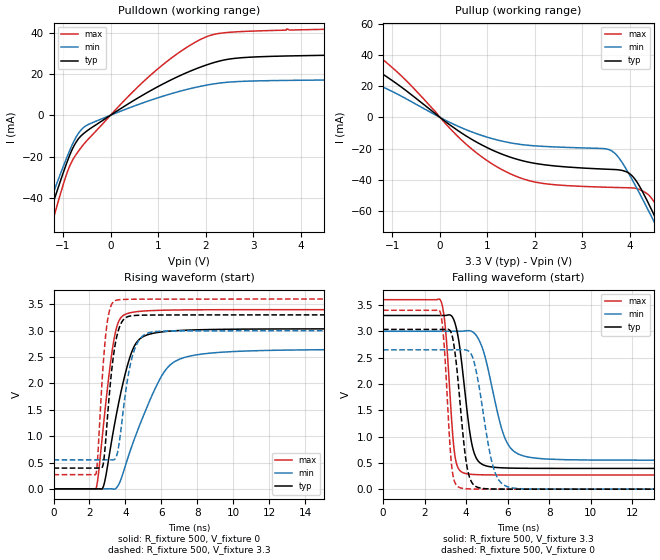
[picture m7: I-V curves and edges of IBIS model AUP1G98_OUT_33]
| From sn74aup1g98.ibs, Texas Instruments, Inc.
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[Model]   AUP1G98_OUT_33
Model_type  Output
Vref =   0
Rref =   1E6
Cref =   30p
Vmeas =   1.65
| variable   typ   min   max
C_comp   2.73pF   1.81pF   4.12pF
| C_pullup   3.12pF   1.81pF   4.12pF
| C_pulldown   2.33pF   2.13pF   2.90pF
[Temperature Range]   40   100   -40
| Ambient temperature   25   85   -40
[Voltage range]   3.3   3   3.6
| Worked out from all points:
|   slope of the pulldown table from 0 to 0.495 V, typ, clamps not added: 68.4 ohm
|   slope of the pullup table from 0 to 0.495 V, typ, clamps not added: 45.8 ohm
|   rising waveform, R_fixture 500, V_fixture 0: 20-80 % time 1.1ns typ, 1.9ns min, 688ps max; typ from 0 V to 3.04 V
|   falling waveform, R_fixture 500, V_fixture 3.3: 20-80 % time 536ps typ, 886ps min, 344ps max; typ from 3.3 V to 0.394 V
|   rising waveform, R_fixture 500, V_fixture 3.3: 20-80 % time 506ps typ, 664ps min, 393ps max; typ from 0.394 V to 3.3 V
|   falling waveform, R_fixture 500, V_fixture 0: 20-80 % time 456ps typ, 684ps min, 305ps max; typ from 3.04 V to 0 V
[Pulldown]
| AUP1G98_OUT_33
|   Voltage   I(typ)   I(min)   I(max)
-3.6V     -218.7mA   -196.3mA   -248.6mA
-1.515V   -64.37mA   -57.31mA   -75.82mA
-1.39V    -55.35mA   -49.29mA   -65.41mA
-1.275V   -47.14mA   -42mA      -55.89mA
-870mV    -19.93mA   -17.62mA   -25.18mA
-720mV    -12.85mA   -10.38mA   -18.82mA
-545mV    -8.444mA   -5.509mA   -13.51mA
940mV     13.13mA    8.018mA    21.36mA
1.5V      19.56mA    11.86mA    31.27mA
2.045V    24.53mA    14.67mA    38.2mA
3.1V      28.27mA    16.63mA    40.81mA
7.2V      29.73mA    17.36mA    42.67mA
[Pullup]
| AUP1G98_OUT_33
|   Voltage   I(typ)   I(min)   I(max)
-3.6V     42.88mA    27.27mA    57.92mA
-2.465V   31.53mA    19.52mA    45.85mA
-1.53V    32.87mA    22.09mA    44.95mA
-755mV    18.1mA     12.64mA    24.89mA
555mV     -11.98mA   -7.942mA   -17.3mA
1.65V     -27.07mA   -17.13mA   -38.31mA
3.61V     -33.32mA   -21.39mA   -44.82mA
4.08V     -38.63mA   -41.77mA   -45.28mA
4.375V    -54.25mA   -58.9mA    -49.24mA
4.565V    -66.24mA   -70.37mA   -57.33mA
4.775V    -80.02mA   -83.29mA   -71.37mA
7.2V      -250.7mA   -240.9mA   -257mA
[Ramp]
| AUP1G98_OUT_33
| variable   typ   min   max
dV/dt_r   1.82/1.10E-09   1.59/1.90E-09   2.04/6.90E-10
dV/dt_f   1.75/5.43E-10   1.48/8.93E-10   2.01/3.48E-10
R_load = 500
[Rising Waveform]
| AUP1G98_OUT_33
R_fixture =   500
C_fixture =   0
L_fixture =   0
V_fixture =   0
V_fixture_min = 0
V_fixture_max = 0
|   Time   V(typ)   V(min)   V(max)
0s        24.73nV    82.54nV    2.123nV
2.365ns   8.968uV    -3.169uV   8.959mV
2.8ns     73.18mV    -19.84uV   1.274V
3.37ns    1.175V     -5.237mV   2.841V
3.655ns   1.678V     100.1mV    3.196V
4.12ns    2.349V     569.7mV    3.327V
4.755ns   2.83V      1.173V     3.366V
6.035ns   2.977V     2.152V     3.388V
7.535ns   3.012V     2.515V     3.395V
30.7ns    3.035V     2.647V     3.399V
[Falling Waveform]
| AUP1G98_OUT_33
R_fixture =   500
C_fixture =   0
L_fixture =   0
V_fixture =   3.3
V_fixture_min = 3
V_fixture_max = 3.6
|   Time   V(typ)   V(min)   V(max)
0s        3.3V       3V         3.6V
2.785ns   3.3V       3V         3.578V
3.015ns   3.301V     3V         3.014V
3.445ns   3.179V     3V         682.3mV
3.92ns    1.933V     3.005V     302.8mV
4.245ns   920.9mV    3.002V     282.1mV
4.575ns   537.6mV    2.868V     274.9mV
5.86ns    403.5mV    978.4mV    269.7mV
6.87ns    396.4mV    620.2mV    269.4mV
30.7ns    394.1mV    550mV      269.3mV
[Rising Waveform]
| AUP1G98_OUT_33
R_fixture =   500
C_fixture =   0
L_fixture =   0
V_fixture =   3.3
V_fixture_min = 3
V_fixture_max = 3.6
|   Time   V(typ)   V(min)   V(max)
0s        394.1mV    550mV      269.3mV
2.36ns    394.1mV    550mV      282.1mV
2.465ns   394.4mV    550mV      632.9mV
2.745ns   437.5mV    550mV      2.264V
2.935ns   1.056V     550.2mV    3.012V
3.22ns    2.194V     550.5mV    3.49V
3.495ns   2.85V      612.5mV    3.578V
4.375ns   3.284V     2.498V     3.597V
5.36ns    3.296V     2.967V     3.599V
30.7ns    3.3V       3V         3.6V
[Falling Waveform]
| AUP1G98_OUT_33
R_fixture =   500
C_fixture =   0
L_fixture =   0
V_fixture =   0
V_fixture_min = 0
V_fixture_max = 0
|   Time   V(typ)   V(min)   V(max)
0s        3.035V     2.647V     3.399V
2.74ns    3.035V     2.647V     3.38V
2.935ns   3.035V     2.647V     2.779V
3.315ns   2.933V     2.647V     407.5mV
3.735ns   1.519V     2.648V     23.26mV
4.005ns   515.7mV    2.643V     8.137mV
4.28ns    124.2mV    2.538V     3.351mV
5.295ns   3.303mV    433.4mV    189.4uV
6.095ns   527.9uV    33.82mV    32.85uV
30.7ns    -26.07nV   45.68nV    -34.58nV
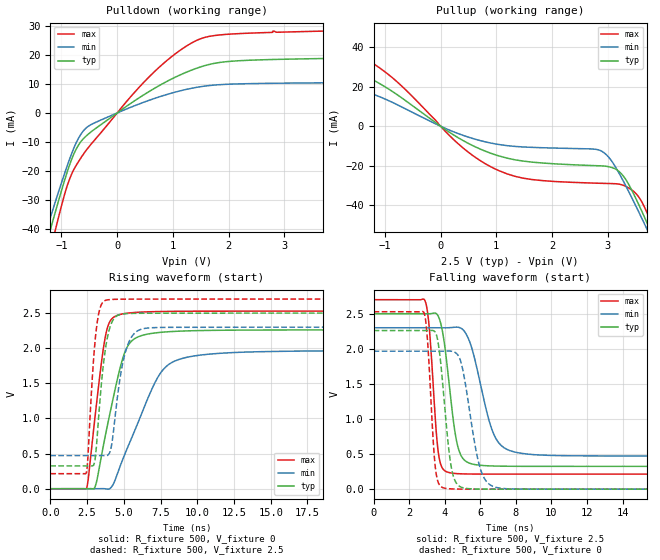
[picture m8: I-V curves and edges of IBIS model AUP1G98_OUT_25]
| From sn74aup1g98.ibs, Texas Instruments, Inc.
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[Model]   AUP1G98_OUT_25
Model_type  Output
Vref =   0
Rref =   1E6
Cref =   30p
Vmeas =   1.25
| variable   typ   min   max
C_comp   2.77pF   1.87pF   4.14pF
| C_pullup   3.12pF   1.87pF   4.14pF
| C_pulldown   2.42pF   2.13pF   2.99pF
[Temperature Range]   40   100   -40
| Ambient temperature   25   85   -40
[Voltage range]   2.5   2.3   2.7
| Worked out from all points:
|   slope of the pulldown table from 0 to 0.375 V, typ, clamps not added: 75.2 ohm
|   slope of the pullup table from 0 to 0.375 V, typ, clamps not added: 55.1 ohm
|   rising waveform, R_fixture 500, V_fixture 0: 20-80 % time 1.4ns typ, 2.39ns min, 856ps max; typ from 0 V to 2.26 V
|   falling waveform, R_fixture 500, V_fixture 2.5: 20-80 % time 625ps typ, 1.07ns min, 396ps max; typ from 2.5 V to 0.325 V
|   rising waveform, R_fixture 500, V_fixture 2.5: 20-80 % time 611ps typ, 786ps min, 469ps max; typ from 0.325 V to 2.5 V
|   falling waveform, R_fixture 500, V_fixture 0: 20-80 % time 515ps typ, 782ps min, 343ps max; typ from 2.26 V to 0 V
[Pulldown]
| AUP1G98_OUT_25
|   Voltage   I(typ)   I(min)   I(max)
-3.6V     -214mA     -193.5mA   -239.7mA
-1.26V    -44.55mA   -39.92mA   -52.42mA
-1.205V   -40.74mA   -36.52mA   -48.02mA
-1.115V   -34.57mA   -31.02mA   -40.91mA
-800mV    -15.22mA   -13.22mA   -20.4mA
-685mV    -10.84mA   -8.445mA   -16.54mA
-540mV    -7.689mA   -4.911mA   -12.5mA
675mV     8.558mA    5.038mA    14.35mA
1.105V    12.9mA     7.5mA      21.28mA
1.52V     16.03mA    9.129mA    25.76mA
2.585V    18.34mA    10.19mA    27.69mA
7.2V      19.61mA    10.73mA    29.61mA
[Pullup]
| AUP1G98_OUT_25
|   Voltage   I(typ)   I(min)   I(max)
-3.6V     37.28mA    23.5mA     50.35mA
-2.355V   24.65mA    15.21mA    35.57mA
-1.425V   26.01mA    17.2mA     35.58mA
-760mV    15.58mA    10.63mA    21.96mA
405mV     -7.279mA   -4.651mA   -11.04mA
1.05V     -15.07mA   -9.293mA   -22.54mA
2.845V    -20.04mA   -12.07mA   -28.88mA
3.17V     -22.17mA   -22.09mA   -29.2mA
3.455V    -33.67mA   -37.48mA   -32.73mA
3.685V    -47.61mA   -50.92mA   -42.5mA
3.82V     -56.28mA   -59.04mA   -51.47mA
7.2V      -294.7mA   -278.7mA   -311.5mA
[Ramp]
| AUP1G98_OUT_25
| variable   typ   min   max
dV/dt_r   1.36/1.40E-09   1.18/2.40E-09   1.52/8.57E-10
dV/dt_f   1.31/6.33E-10   1.10/1.07E-09   1.50/4.06E-10
R_load = 500
[Rising Waveform]
| AUP1G98_OUT_25
R_fixture =   500
C_fixture =   0
L_fixture =   0
V_fixture =   0
V_fixture_min = 0
V_fixture_max = 0
|   Time   V(typ)   V(min)   V(max)
0s        19.04nV    76.96nV    1.464nV
2.47ns    -20.63uV   43.8nV     8.222mV
3.07ns    40.86mV    -29.67uV   1.068V
3.72ns    727.7mV    -199.1uV   2.134V
4.575ns   1.568V     217.8mV    2.469V
5.105ns   1.959V     508.2mV    2.495V
5.66ns    2.125V     784.2mV    2.508V
7.42ns    2.224V     1.622V     2.522V
8.905ns   2.244V     1.851V     2.526V
32.79ns   2.261V     1.966V     2.528V
[Falling Waveform]
| AUP1G98_OUT_25
R_fixture =   500
C_fixture =   0
L_fixture =   0
V_fixture =   2.5
V_fixture_min = 2.3
V_fixture_max = 2.7
|   Time   V(typ)   V(min)   V(max)
0s        2.5V       2.3V       2.7V
2.895ns   2.5V       2.3V       2.683V
3.135ns   2.499V     2.3V       2.285V
3.64ns    2.463V     2.3V       519.8mV
4.2ns     1.612V     2.3V       239.2mV
4.615ns   753.7mV    2.308V     222.8mV
5.005ns   443mV      2.277V     217.9mV
6.73ns    330.1mV    800mV      214.5mV
7.895ns   326mV      531.8mV    214.4mV
32.79ns   324.7mV    472mV      214.4mV
[Rising Waveform]
| AUP1G98_OUT_25
R_fixture =   500
C_fixture =   0
L_fixture =   0
V_fixture =   2.5
V_fixture_min = 2.3
V_fixture_max = 2.7
|   Time   V(typ)   V(min)   V(max)
0s        324.7mV    472mV      214.4mV
2.455ns   324.7mV    472mV      227.4mV
2.945ns   332.9mV    472mV      1.838V
3.115ns   545.3mV    472mV      2.238V
3.39ns    1.282V     472.4mV    2.574V
3.77ns    2.015V     471.1mV    2.682V
4.15ns    2.35V      596.9mV    2.694V
5.11ns    2.492V     1.944V     2.698V
6.205ns   2.498V     2.272V     2.699V
32.79ns   2.5V       2.3V       2.7V
[Falling Waveform]
| AUP1G98_OUT_25
R_fixture =   500
C_fixture =   0
L_fixture =   0
V_fixture =   0
V_fixture_min = 0
V_fixture_max = 0
|   Time   V(typ)   V(min)   V(max)
0s        2.261V     1.966V     2.528V
2.835ns   2.261V     1.966V     2.512V
3.035ns   2.26V      1.966V     2.105V
3.47ns    2.234V     1.966V     312.7mV
3.945ns   1.331V     1.966V     17.07mV
4.29ns    441.5mV    1.968V     5.176mV
4.615ns   101.5mV    1.944V     1.881mV
5.985ns   1.381mV    306.3mV    53.78uV
6.87ns    238.3uV    25.85mV    10.3uV
32.79ns   -19.76nV   27.44nV    -30.47nV
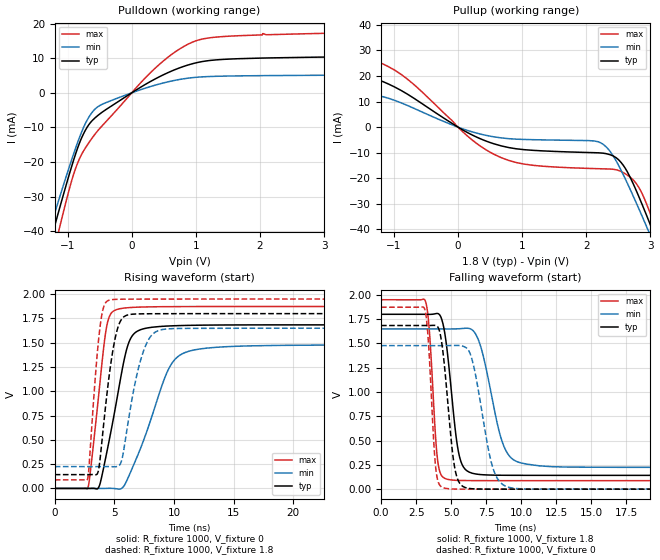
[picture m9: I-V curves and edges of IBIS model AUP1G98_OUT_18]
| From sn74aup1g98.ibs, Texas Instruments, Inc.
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[Model]   AUP1G98_OUT_18
Model_type  Output
Vref =   0
Rref =   1E6
Cref =   30p
Vmeas =   0.9
| variable   typ   min   max
C_comp   2.80pF   1.94pF   4.08pF
| C_pullup   3.08pF   1.94pF   4.08pF
| C_pulldown   2.52pF   2.14pF   3.04pF
[Temperature Range]   40   100   -40
| Ambient temperature   25   85   -40
[Voltage range]   1.8   1.65   1.95
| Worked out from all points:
|   slope of the pulldown table from 0 to 0.27 V, typ, clamps not added: 88.6 ohm
|   slope of the pullup table from 0 to 0.27 V, typ, clamps not added: 73.6 ohm
|   rising waveform, R_fixture 1000, V_fixture 0: 20-80 % time 1.56ns typ, 2.57ns min, 978ps max; typ from 0 V to 1.68 V
|   falling waveform, R_fixture 1000, V_fixture 1.8: 20-80 % time 738ps typ, 1.29ns min, 457ps max; typ from 1.8 V to 0.142 V
|   rising waveform, R_fixture 1000, V_fixture 1.8: 20-80 % time 996ps typ, 1.38ns min, 709ps max; typ from 0.142 V to 1.8 V
|   falling waveform, R_fixture 1000, V_fixture 0: 20-80 % time 667ps typ, 1.1ns min, 424ps max; typ from 1.68 V to 0 V
[Pulldown]
| AUP1G98_OUT_18
|   Voltage   I(typ)   I(min)   I(max)
-3.6V     -208.6mA   -189.9mA   -231.7mA
-1.27V    -43.16mA   -39.01mA   -50.14mA
-1.215V   -39.42mA   -35.66mA   -45.88mA
-1.125V   -33.38mA   -30.25mA   -38.97mA
-850mV    -16.31mA   -14.68mA   -20.63mA
-710mV    -10.41mA   -8.408mA   -15.6mA
-555mV    -6.973mA   -4.411mA   -11.55mA
360mV     3.96mA     2.185mA    7.039mA
705mV     6.927mA    3.722mA    12.18mA
1.03V     8.784mA    4.527mA    15.22mA
2.04V     10.05mA    4.966mA    17.1mA
7.2V      11.18mA    5.355mA    18.77mA
[Pullup]
| AUP1G98_OUT_18
|   Voltage   I(typ)   I(min)   I(max)
-3.6V     32.09mA    19.71mA    43.84mA
-3.16V    27.19mA    16.62mA    37.96mA
-2.12V    17.93mA    10.78mA    26.5mA
-1.525V   19.29mA    11.78mA    27.75mA
-1.155V   17.65mA    11.82mA    24.55mA
680mV     -7.373mA   -4.228mA   -12mA
2.185V    -10.05mA   -5.721mA   -16.26mA
2.485V    -12.35mA   -14.1mA    -16.81mA
2.725V    -21.81mA   -26.61mA   -20.47mA
2.94V     -34.55mA   -38.91mA   -30.08mA
3.085V    -43.74mA   -47.5mA    -39.77mA
7.2V      -334.8mA   -315.6mA   -357.6mA
[Ramp]
| AUP1G98_OUT_18
| variable   typ   min   max
dV/dt_r   1.01/1.56E-09   0.89/2.58E-09   1.13/9.81E-10
dV/dt_f   1.00/7.45E-10   0.86/1.30E-09   1.12/4.62E-10
R_load = 1000
[Rising Waveform]
| AUP1G98_OUT_18
R_fixture =   1000
C_fixture =   0
L_fixture =   0
V_fixture =   0
V_fixture_min = 0
V_fixture_max = 0
|   Time   V(typ)   V(min)   V(max)
0s        17.12nV    87.22nV    1.127nV
2.78ns    -23.81uV   -36.59nV   7.813mV
3.67ns    8.984mV    -20.25uV   948.4mV
4.275ns   319.6mV    376.1uV    1.613V
5.095ns   841mV      -2.406mV   1.838V
5.95ns    1.396V     57.58mV    1.859V
6.58ns    1.585V     232mV      1.865V
9.45ns    1.672V     1.206V     1.872V
10.94ns   1.678V     1.4V       1.873V
35.9ns    1.685V     1.477V     1.873V
[Falling Waveform]
| AUP1G98_OUT_18
R_fixture =   1000
C_fixture =   0
L_fixture =   0
V_fixture =   1.8
V_fixture_min = 1.65
V_fixture_max = 1.95
|   Time   V(typ)   V(min)   V(max)
0s        1.8V       1.65V      1.95V
3.165ns   1.8V       1.65V      1.936V
3.445ns   1.799V     1.65V      1.635V
4.02ns    1.808V     1.65V      319.3mV
4.62ns    1.537V     1.649V     107mV
5.52ns    387.2mV    1.651V     90mV
6.46ns    166.2mV    1.644V     88.23mV
8.665ns   143.2mV    479.3mV    87.9mV
9.805ns   142.5mV    277.6mV    87.9mV
35.9ns    142.2mV    224.7mV    87.89mV
[Rising Waveform]
| AUP1G98_OUT_18
R_fixture =   1000
C_fixture =   0
L_fixture =   0
V_fixture =   1.8
V_fixture_min = 1.65
V_fixture_max = 1.95
|   Time   V(typ)   V(min)   V(max)
0s        142.2mV    224.7mV    87.89mV
2.76ns    142.2mV    224.7mV    99.88mV
3.755ns   257.7mV    224.7mV    1.622V
4.08ns    638.5mV    224.8mV    1.861V
4.505ns   1.107V     225.3mV    1.936V
5.07ns    1.55V      223.2mV    1.947V
5.62ns    1.745V     294.3mV    1.948V
7.175ns   1.798V     1.311V     1.95V
8.695ns   1.799V     1.626V     1.95V
35.9ns    1.8V       1.65V      1.95V
[Falling Waveform]
| AUP1G98_OUT_18
R_fixture =   1000
C_fixture =   0
L_fixture =   0
V_fixture =   0
V_fixture_min = 0
V_fixture_max = 0
|   Time   V(typ)   V(min)   V(max)
0s        1.685V     1.478V     1.873V
3.125ns   1.684V     1.478V     1.849V
3.375ns   1.684V     1.478V     1.525V
3.89ns    1.685V     1.477V     235.9mV
4.42ns    1.409V     1.477V     15.75mV
5.225ns   246.8mV    1.48V      1.38mV
6.03ns    15.68mV    1.46V      150.6uV
7.95ns    215.4uV    233.2mV    3.425uV
9.02ns    44.82uV    23.16mV    655.1nV
35.9ns    7.596nV    48.19nV    -58.74nV
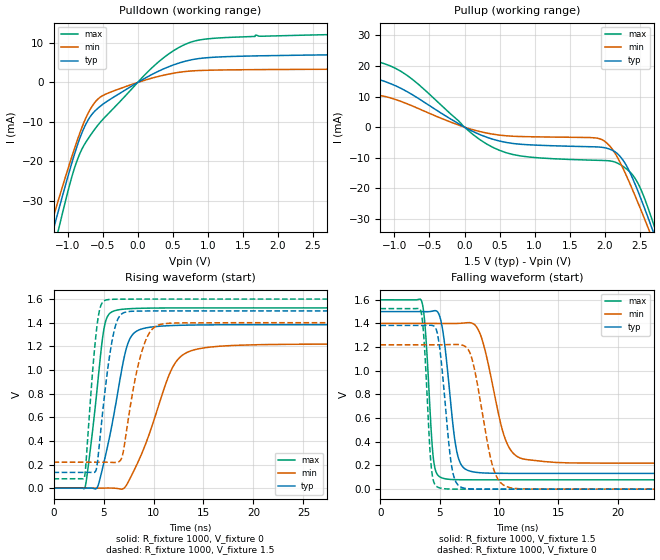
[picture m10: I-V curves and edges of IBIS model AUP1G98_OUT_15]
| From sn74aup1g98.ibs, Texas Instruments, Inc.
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[Model]   AUP1G98_OUT_15
Model_type  Output
Vref =   0
Rref =   1E6
Cref =   30p
Vmeas =   0.75
| variable   typ   min   max
C_comp   2.79pF   1.99pF   4.00pF
| C_pullup   3.03pF   1.99pF   4.00pF
| C_pulldown   2.56pF   2.15pF   3.05pF
[Temperature Range]   40   100   -40
| Ambient temperature   25   85   -40
[Voltage range]   1.5   1.4   1.6
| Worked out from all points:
|   slope of the pulldown table from 0 to 0.225 V, typ, clamps not added: 101 ohm
|   slope of the pullup table from 0 to 0.225 V, typ, clamps not added: 90.4 ohm
|   rising waveform, R_fixture 1000, V_fixture 0: 20-80 % time 1.86ns typ, 3.07ns min, 1.18ns max; typ from 0 V to 1.38 V
|   falling waveform, R_fixture 1000, V_fixture 1.5: 20-80 % time 874ps typ, 1.57ns min, 528ps max; typ from 1.5 V to 0.133 V
|   rising waveform, R_fixture 1000, V_fixture 1.5: 20-80 % time 1.19ns typ, 1.61ns min, 855ps max; typ from 0.133 V to 1.5 V
|   falling waveform, R_fixture 1000, V_fixture 0: 20-80 % time 790ps typ, 1.33ns min, 489ps max; typ from 1.38 V to 0 V
[Pulldown]
| AUP1G98_OUT_15
|   Voltage   I(typ)   I(min)   I(max)
-3.6V     -206.1mA   -188.4mA   -227.8mA
-1.265V   -41.59mA   -37.94mA   -47.65mA
-1.21V    -37.9mA    -34.62mA   -43.48mA
-1.11V    -31.29mA   -28.67mA   -36mA
-945mV    -20.84mA   -19.21mA   -24.37mA
-855mV    -15.7mA    -14.39mA   -19.43mA
-720mV    -9.972mA   -8.297mA   -14.65mA
-570mV    -6.595mA   -4.269mA   -10.91mA
260mV     2.544mA    1.373mA    4.642mA
810mV     5.906mA    2.979mA    10.53mA
1.685V    6.762mA    3.268mA    12.01mA
7.2V      7.827mA    3.609mA    13.77mA
[Pullup]
| AUP1G98_OUT_15
|   Voltage   I(typ)   I(min)   I(max)
-3.6V     29.66mA    17.95mA    40.7mA
-2.925V   22.54mA    13.64mA    31.9mA
-2.13V    15.77mA    9.503mA    23.16mA
-1.025V   13.91mA    9.322mA    19.64mA
130mV     -1.525mA   -910.1uA   -2.565mA
590mV     -4.979mA   -2.819mA   -8.32mA
1.925V    -6.506mA   -3.765mA   -10.85mA
2.175V    -8.513mA   -9.57mA    -11.67mA
2.395V    -16.55mA   -20.31mA   -15.49mA
2.615V    -29.32mA   -32.63mA   -26.15mA
2.72V     -35.89mA   -38.74mA   -33.2mA
7.2V      -352.6mA   -330.3mA   -379.5mA
[Ramp]
| AUP1G98_OUT_15
| variable   typ   min   max
dV/dt_r   0.83/1.88E-09   0.74/3.10E-09   0.92/1.19E-09
dV/dt_f   0.83/8.82E-10   0.71/1.58E-09   0.92/5.32E-10
R_load = 1000
[Rising Waveform]
| AUP1G98_OUT_15
R_fixture =   1000
C_fixture =   0
L_fixture =   0
V_fixture =   0
V_fixture_min = 0
V_fixture_max = 0
|   Time   V(typ)   V(min)   V(max)
0s        16.57nV    92.2nV     986.7pV
3.15ns    -28.21uV   -326.5nV   7.591mV
4.34ns    1.184mV    -21.34uV   823.4mV
4.98ns    196.1mV    129.5uV    1.315V
5.865ns   544mV      487.9uV    1.493V
7.095ns   1.118V     3.103mV    1.515V
7.845ns   1.293V     114.4mV    1.519V
11.69ns   1.375V     984mV      1.525V
13.32ns   1.379V     1.147V     1.525V
34.99ns   1.383V     1.22V      1.525V
[Falling Waveform]
| AUP1G98_OUT_15
R_fixture =   1000
C_fixture =   0
L_fixture =   0
V_fixture =   1.5
V_fixture_min = 1.4
V_fixture_max = 1.6
|   Time   V(typ)   V(min)   V(max)
0s        1.5V       1.4V       1.6V
3.48ns    1.5V       1.4V       1.587V
4.46ns    1.506V     1.4V       266.7mV
5.125ns   1.413V     1.4V       98mV
6.375ns   352.5mV    1.4V       80.25mV
7.33ns    160.4mV    1.407V     79.28mV
8.425ns   138.7mV    1.308V     79.11mV
10.4ns    133.6mV    459mV      79.08mV
11.74ns   133.3mV    264.8mV    79.08mV
34.99ns   133.1mV    219.3mV    79.08mV
[Rising Waveform]
| AUP1G98_OUT_15
R_fixture =   1000
C_fixture =   0
L_fixture =   0
V_fixture =   1.5
V_fixture_min = 1.4
V_fixture_max = 1.6
|   Time   V(typ)   V(min)   V(max)
0s        133.1mV    219.3mV    79.08mV
3.07ns    133.1mV    219.3mV    84.58mV
4.27ns    156.7mV    219.3mV    1.317V
5.11ns    793.5mV    219.6mV    1.587V
5.86ns    1.247V     217.8mV    1.598V
6.545ns   1.448V     224.3mV    1.599V
6.95ns    1.482V     298mV      1.599V
8.72ns    1.499V     1.124V     1.6V
10.37ns   1.5V       1.376V     1.6V
34.99ns   1.5V       1.4V       1.6V
[Falling Waveform]
| AUP1G98_OUT_15
R_fixture =   1000
C_fixture =   0
L_fixture =   0
V_fixture =   0
V_fixture_min = 0
V_fixture_max = 0
|   Time   V(typ)   V(min)   V(max)
0s        1.383V     1.22V      1.525V
3.4ns     1.383V     1.22V      1.508V
4.29ns    1.384V     1.22V      185.8mV
4.88ns    1.274V     1.219V     14.87mV
5.98ns    211.4mV    1.222V     729.6uV
6.825ns   15.66mV    1.219V     83.1uV
7.775ns   1.711mV    1.08V      11.98uV
9.52ns    82.62uV    176.5mV    900.4nV
10.6ns    20.7uV     22.8mV     289.2nV
34.99ns   -21.64nV   53.06nV    -50.8nV
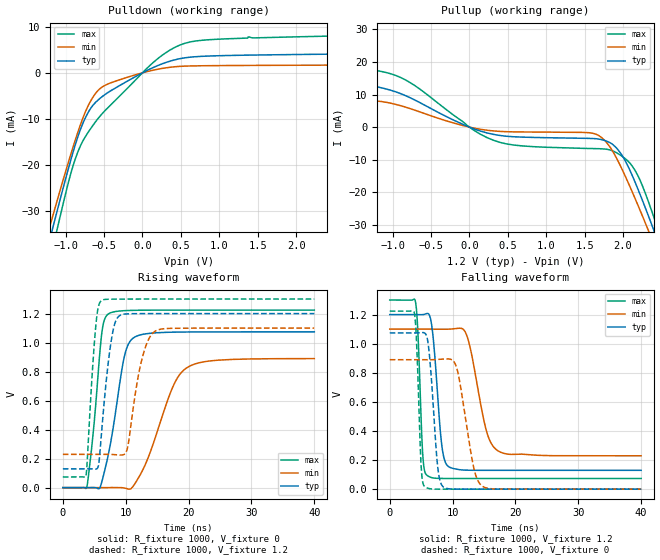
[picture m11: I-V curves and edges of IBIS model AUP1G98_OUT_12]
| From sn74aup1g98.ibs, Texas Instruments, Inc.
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[Model]   AUP1G98_OUT_12
Model_type  Output
Vref =   0
Rref =   1E6
Cref =   30p
Vmeas =   0.6
| variable   typ   min   max
C_comp   2.77pF   2.03pF   3.84pF
| C_pullup   2.95pF   2.03pF   3.84pF
| C_pulldown   2.59pF   2.14pF   3.08pF
[Temperature Range]   40   100   -40
| Ambient temperature   25   85   -40
[Voltage range]   1.2   1.1   1.3
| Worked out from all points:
|   slope of the pulldown table from 0 to 0.18 V, typ, clamps not added: 125 ohm
|   slope of the pullup table from 0 to 0.18 V, typ, clamps not added: 123 ohm
|   rising waveform, R_fixture 1000, V_fixture 0: 20-80 % time 2.41ns typ, 4.38ns min, 1.48ns max; typ from 0 V to 1.07 V
|   falling waveform, R_fixture 1000, V_fixture 1.2: 20-80 % time 1.14ns typ, 2.34ns min, 646ps max; typ from 1.2 V to 0.129 V
|   rising waveform, R_fixture 1000, V_fixture 1.2: 20-80 % time 1.51ns typ, 2.09ns min, 1.07ns max; typ from 0.129 V to 1.2 V
|   falling waveform, R_fixture 1000, V_fixture 0: 20-80 % time 1.05ns typ, 1.98ns min, 601ps max; typ from 1.07 V to 0 V
[Pulldown]
| AUP1G98_OUT_12
|   Voltage   I(typ)   I(min)   I(max)
-3.6V     -203.6mA   -186.6mA   -224.6mA
-1.215V   -36.77mA   -33.88mA   -41.55mA
-1.165V   -33.49mA   -30.92mA   -37.89mA
-1.12V    -30.57mA   -28.28mA   -34.63mA
-1.08V    -28mA      -25.95mA   -31.76mA
-930mV    -18.76mA   -17.53mA   -21.68mA
-820mV    -12.87mA   -11.86mA   -16.33mA
-695mV    -8.261mA   -6.747mA   -12.62mA
-580mV    -5.938mA   -3.862mA   -9.962mA
160mV     1.298mA    643.5uA    2.533mA
610mV     3.376mA    1.481mA    6.659mA
7.2V      4.761mA    1.852mA    9.574mA
[Pullup]
| AUP1G98_OUT_12
|   Voltage   I(typ)   I(min)   I(max)
-3.6V     26.64mA    8.226mA    37.8mA
-3.065V   21.41mA    10.49mA    30.92mA
-2.05V    13.06mA    7.529mA    19.66mA
-955mV    10.79mA    6.951mA    15.81mA
400mV     -2.561mA   -1.314mA   -4.679mA
1.61V     -3.491mA   -1.891mA   -6.566mA
1.87V     -5.387mA   -7.563mA   -7.321mA
2.095V    -13.49mA   -18.49mA   -11.17mA
2.33V     -27.16mA   -31.66mA   -22.8mA
2.44V     -34.07mA   -38.08mA   -30.25mA
2.51V     -38.55mA   -42.22mA   -35.17mA
7.2V      -371mA     -348.5mA   -398.6mA
[Ramp]
| AUP1G98_OUT_12
| variable   typ   min   max
dV/dt_r   0.65/2.43E-09   0.54/4.44E-09   0.74/1.49E-09
dV/dt_f   0.65/1.15E-09   0.53/2.35E-09   0.74/6.51E-10
R_load = 1000
[Rising Waveform]
| AUP1G98_OUT_12
R_fixture =   1000
C_fixture =   0
L_fixture =   0
V_fixture =   0
V_fixture_min = 0
V_fixture_max = 0
|   Time   V(typ)   V(min)   V(max)
0s        17.04nV    106.6nV    899pV
3.805ns   -18.26uV   23.67nV    2.899mV
4.855ns   495.2uV    228.2nV    389.6mV
6.18ns    37.15mV    -16.22uV   1.06V
7.225ns   226.2mV    125.3uV    1.197V
9.76ns    898.9mV    -2.433mV   1.22V
11.39ns   1.037V     22.46mV    1.222V
17.54ns   1.072V     698.7mV    1.224V
19.62ns   1.073V     823.5mV    1.224V
40ns      1.074V     889.6mV    1.224V
[Falling Waveform]
| AUP1G98_OUT_12
R_fixture =   1000
C_fixture =   0
L_fixture =   0
V_fixture =   1.2
V_fixture_min = 1.1
V_fixture_max = 1.3
|   Time   V(typ)   V(min)   V(max)
0s        1.2V       1.1V       1.3V
4.08ns    1.2V       1.1V       1.291V
5.27ns    1.2V       1.1V       226.4mV
6ns       1.208V     1.1V       92.82mV
6.845ns   1.068V     1.1V       77.57mV
8.325ns   287.7mV    1.1V       73.79mV
9.33ns    155.6mV    1.1V       73.59mV
12.19ns   130.7mV    1.064V     73.54mV
17.19ns   129.5mV    264.2mV    73.54mV
40ns      129.5mV    229.3mV    73.54mV
[Rising Waveform]
| AUP1G98_OUT_12
R_fixture =   1000
C_fixture =   0
L_fixture =   0
V_fixture =   1.2
V_fixture_min = 1.1
V_fixture_max = 1.3
|   Time   V(typ)   V(min)   V(max)
0s        129.5mV    229.3mV    73.54mV
3.67ns    129.5mV    229.3mV    79.48mV
5.18ns    127.8mV    229.3mV    1.086V
6.135ns   367.9mV    229.3mV    1.29V
7.68ns    1.008V     229.2mV    1.299V
9.095ns   1.188V     225mV      1.3V
10.23ns   1.198V     265.1mV    1.3V
12.46ns   1.2V       864.7mV    1.3V
14.66ns   1.2V       1.078V     1.3V
40ns      1.2V       1.1V       1.3V
[Falling Waveform]
| AUP1G98_OUT_12
R_fixture =   1000
C_fixture =   0
L_fixture =   0
V_fixture =   0
V_fixture_min = 0
V_fixture_max = 0
|   Time   V(typ)   V(min)   V(max)
0s        1.074V     889.8mV    1.224V
3.945ns   1.074V     889.8mV    1.204V
5.01ns    1.076V     889.8mV    150.2mV
5.62ns    1.071V     889.7mV    15.47mV
6.325ns   917.4mV    889.6mV    3.696mV
7.67ns    139.5mV    892.1mV    143.5uV
8.585ns   13mV       894.1mV    19.29uV
10.66ns   318.5uV    833.5mV    714nV
14.77ns   2.489uV    18.98mV    -43.91nV
40ns      -13.74nV   85.05nV    -43.97nV
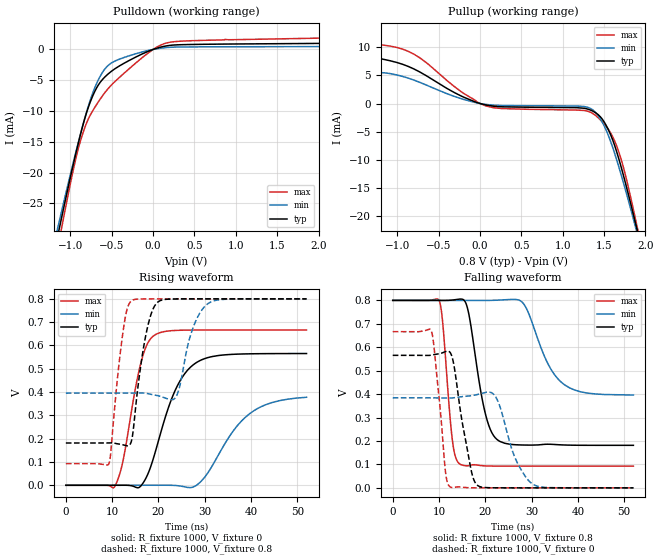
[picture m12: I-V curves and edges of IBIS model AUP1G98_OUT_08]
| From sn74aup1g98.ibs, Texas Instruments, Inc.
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[Model]   AUP1G98_OUT_08
Model_type  Output
Vref =   0
Rref =   1E6
Cref =   30p
Vmeas =   0.4
| variable   typ   min   max
C_comp   2.62pF   2.11pF   3.26pF
| C_pullup   2.68pF   2.11pF   3.26pF
| C_pulldown   2.55pF   2.11pF   2.99pF
[Temperature Range]   40   100   -40
| Ambient temperature   25   85   -40
[Voltage range]   0.8   0.8   0.8
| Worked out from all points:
|   slope of the pulldown table from 0 to 0.12 V, typ, clamps not added: 257 ohm
|   slope of the pullup table from 0 to 0.12 V, typ, clamps not added: 309 ohm
|   rising waveform, R_fixture 1000, V_fixture 0: 20-80 % time 5.93ns typ, 8.01ns min, 3.69ns max; typ from 0 V to 0.565 V
|   falling waveform, R_fixture 1000, V_fixture 0.8: 20-80 % time 3.16ns typ, 5.34ns min, 1.71ns max; typ from 0.8 V to 0.181 V
|   rising waveform, R_fixture 1000, V_fixture 0.8: 20-80 % time 2.7ns typ, 3.27ns min, 2.25ns max; typ from 0.181 V to 0.8 V
|   falling waveform, R_fixture 1000, V_fixture 0: 20-80 % time 2.81ns typ, 4ns min, 1.83ns max; typ from 0.566 V to 0 V
[Pulldown]
| AUP1G98_OUT_08
|   Voltage   I(typ)   I(min)   I(max)
-3.6V     -200.3mA   -184.7mA   -219.1mA
-1.155V   -30.43mA   -29.11mA   -32.45mA
-1.105V   -27.26mA   -26.22mA   -28.93mA
-940mV    -17.24mA   -17.01mA   -18.09mA
-865mV    -13.13mA   -13.1mA    -14.27mA
-745mV    -8.043mA   -7.657mA   -10.32mA
-630mV    -5.174mA   -4.128mA   -7.88mA
-470mV    -3.218mA   -1.946mA   -5.328mA
5mV       23.8uA     12.51uA    45.54uA
245mV     711.3uA    371.9uA    1.246mA
870mV     872.1uA    431.7uA    1.618mA
7.2V      1.459mA    578.6uA    3.138mA
[Pullup]
| AUP1G98_OUT_08
|   Voltage   I(typ)   I(min)   I(max)
-3.6V     2.784mA    339.2uA    9.474mA
-2.56V    3.921mA    663.8uA    11.14mA
-2.01V    6.261mA    1.269mA    13.37mA
-1.185V   7.906mA    5.477mA    10.41mA
-800mV    6.149mA    4.169mA    8.776mA
80mV      -287uA     -177.3uA   -461.9uA
1.285V    -921uA     -607uA     -1.305mA
1.455V    -2.355mA   -2.736mA   -2.902mA
1.625V    -7.333mA   -8.725mA   -6.56mA
1.74V     -13.09mA   -14.38mA   -11.68mA
1.905V    -22.78mA   -23.32mA   -22.23mA
7.2V      -396.8mA   -367.4mA   -431.7mA
[Ramp]
| AUP1G98_OUT_08
| variable   typ   min   max
dV/dt_r   0.35/5.99E-09   0.23/8.13E-09   0.41/3.74E-09
dV/dt_f   0.37/3.17E-09   0.24/5.36E-09   0.43/1.72E-09
R_load = 1000
[Rising Waveform]
| AUP1G98_OUT_08
R_fixture =   1000
C_fixture =   0
L_fixture =   0
V_fixture =   0
V_fixture_min = 0
V_fixture_max = 0
|   Time   V(typ)   V(min)   V(max)
0s        23.71nV    153.5nV    1.008nV
10.58ns   293.4uV    -25.4nV    -4.717mV
12.33ns   197uV      -1.998uV   103.3mV
16.28ns   -999.3uV   29.67uV    530.8mV
17.63ns   44.12mV    275.6uV    607.3mV
19.2ns    134.1mV    111.4uV    644.6mV
23.58ns   405.6mV    -750.2uV   664.4mV
28.07ns   524.8mV    -1.837mV   666.2mV
39.45ns   564mV      303.2mV    666.5mV
52ns      565.4mV    377.7mV    666.5mV
[Falling Waveform]
| AUP1G98_OUT_08
R_fixture =   1000
C_fixture =   0
L_fixture =   0
V_fixture =   0.8
V_fixture_min = 0.8
V_fixture_max = 0.8
|   Time   V(typ)   V(min)   V(max)
0s        800mV      800mV      800mV
10.07ns   799.8mV    800mV      797.7mV
12.9ns    801.5mV    799.9mV    201.9mV
14.48ns   805.4mV    799.8mV    101.9mV
16.14ns   767.7mV    799.9mV    94mV
19.76ns   337.3mV    799.7mV    93.93mV
22.52ns   206.5mV    800.9mV    92.79mV
28.22ns   182.8mV    786.7mV    92.73mV
37.23ns   182.8mV    438.2mV    92.72mV
52ns      181.5mV    396mV      92.72mV
[Rising Waveform]
| AUP1G98_OUT_08
R_fixture =   1000
C_fixture =   0
L_fixture =   0
V_fixture =   0.8
V_fixture_min = 0.8
V_fixture_max = 0.8
|   Time   V(typ)   V(min)   V(max)
0s        181.5mV    395.5mV    92.72mV
9.345ns   181.8mV    395.5mV    94.49mV
12.32ns   173.8mV    395.5mV    654.5mV
14.24ns   195.6mV    395.7mV    792.5mV
17.12ns   627.7mV    395.4mV    799.8mV
19.88ns   786.5mV    384.5mV    800mV
23.87ns   799.6mV    382mV      800mV
27.3ns    799.9mV    666.4mV    800mV
30.84ns   800mV      781.5mV    800mV
52ns      800mV      800mV      800mV
[Falling Waveform]
| AUP1G98_OUT_08
R_fixture =   1000
C_fixture =   0
L_fixture =   0
V_fixture =   0
V_fixture_min = 0
V_fixture_max = 0
|   Time   V(typ)   V(min)   V(max)
0s        565.5mV    384mV      666.5mV
8.36ns    566.4mV    384mV      667.8mV
11.41ns   581.4mV    383.3mV    67.36mV
12.39ns   577.9mV    383.3mV    4.206mV
16.9ns    79.58mV    393.2mV    350.2uV
18.36ns   9.785mV    398.7mV    55.12uV
22.25ns   207.9uV    387.9mV    958.8nV
26.46ns   10.39uV    126.7mV    39.42nV
30.32ns   1.378uV    15.02mV    -96.92nV
52ns      153.4nV    1.319uV    -40.32nV
